VERSION 5.7 ;
  NOWIREEXTENSIONATPIN ON ;
  DIVIDERCHAR "/" ;
  BUSBITCHARS "[]" ;
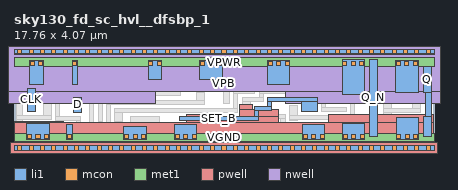
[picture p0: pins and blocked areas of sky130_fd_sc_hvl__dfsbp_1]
MACRO sky130_fd_sc_hvl__dfsbp_1
  CLASS BLOCK ;
  FOREIGN sky130_fd_sc_hvl__dfsbp_1 ;
  ORIGIN 0.000 0.000 ;
  SIZE 17.760 BY 4.070 ;
  PIN CLK
    ANTENNAGATEAREA 0.585000 ;
    PORT
      LAYER li1 ;
        RECT 0.560 1.550 0.890 2.520 ;
    END
  END CLK
  PIN D
    ANTENNAGATEAREA 0.420000 ;
    PORT
      LAYER li1 ;
        RECT 2.525 1.515 2.875 2.145 ;
    END
  END D
  PIN SET_B
    ANTENNAGATEAREA 0.840000 ;
    PORT
      LAYER li1 ;
        RECT 10.715 1.975 12.830 2.145 ;
        RECT 10.715 1.775 10.885 1.975 ;
        RECT 10.160 1.605 10.885 1.775 ;
        RECT 10.160 1.325 10.330 1.605 ;
        RECT 12.150 1.555 12.830 1.975 ;
        RECT 6.985 1.155 10.330 1.325 ;
    END
  END SET_B
  PIN VGND
    USE GROUND ;
    PORT
      LAYER li1 ;
        RECT 0.540 0.365 1.490 1.020 ;
        RECT 2.220 0.365 2.470 0.985 ;
        RECT 4.650 0.365 5.600 0.905 ;
        RECT 6.785 0.365 7.735 0.975 ;
        RECT 12.200 0.365 13.150 0.975 ;
        RECT 13.900 0.365 14.835 1.025 ;
        RECT 16.155 0.365 17.105 1.305 ;
      LAYER mcon ;
        RECT 0.570 0.395 0.740 0.565 ;
        RECT 0.930 0.395 1.100 0.565 ;
        RECT 1.290 0.395 1.460 0.565 ;
        RECT 2.250 0.395 2.420 0.565 ;
        RECT 4.680 0.395 4.850 0.565 ;
        RECT 5.040 0.395 5.210 0.565 ;
        RECT 5.400 0.395 5.570 0.565 ;
        RECT 6.815 0.395 6.985 0.565 ;
        RECT 7.175 0.395 7.345 0.565 ;
        RECT 7.535 0.395 7.705 0.565 ;
        RECT 12.230 0.395 12.400 0.565 ;
        RECT 12.590 0.395 12.760 0.565 ;
        RECT 12.950 0.395 13.120 0.565 ;
        RECT 13.920 0.395 14.090 0.565 ;
        RECT 14.280 0.395 14.450 0.565 ;
        RECT 14.640 0.395 14.810 0.565 ;
        RECT 16.185 0.395 16.355 0.565 ;
        RECT 16.545 0.395 16.715 0.565 ;
        RECT 16.905 0.395 17.075 0.565 ;
      LAYER met1 ;
        RECT 0.000 0.255 17.760 0.625 ;
    END
  END VGND
  PIN VNB
    ANTENNADIFFAREA 3.019200 ;
    PORT
      LAYER pwell ;
        RECT 9.540 1.645 10.090 1.845 ;
        RECT 7.315 1.315 8.605 1.415 ;
        RECT 9.540 1.315 11.200 1.645 ;
        RECT 0.020 1.095 2.090 1.110 ;
        RECT 0.020 1.085 5.690 1.095 ;
        RECT 7.315 1.085 11.200 1.315 ;
        RECT 13.280 1.085 17.740 1.415 ;
        RECT 0.020 0.215 17.740 1.085 ;
        RECT -0.130 -0.215 17.890 0.215 ;
      LAYER li1 ;
        RECT 0.000 -0.085 17.760 0.085 ;
      LAYER mcon ;
        RECT 0.155 -0.085 0.325 0.085 ;
        RECT 0.635 -0.085 0.805 0.085 ;
        RECT 1.115 -0.085 1.285 0.085 ;
        RECT 1.595 -0.085 1.765 0.085 ;
        RECT 2.075 -0.085 2.245 0.085 ;
        RECT 2.555 -0.085 2.725 0.085 ;
        RECT 3.035 -0.085 3.205 0.085 ;
        RECT 3.515 -0.085 3.685 0.085 ;
        RECT 3.995 -0.085 4.165 0.085 ;
        RECT 4.475 -0.085 4.645 0.085 ;
        RECT 4.955 -0.085 5.125 0.085 ;
        RECT 5.435 -0.085 5.605 0.085 ;
        RECT 5.915 -0.085 6.085 0.085 ;
        RECT 6.395 -0.085 6.565 0.085 ;
        RECT 6.875 -0.085 7.045 0.085 ;
        RECT 7.355 -0.085 7.525 0.085 ;
        RECT 7.835 -0.085 8.005 0.085 ;
        RECT 8.315 -0.085 8.485 0.085 ;
        RECT 8.795 -0.085 8.965 0.085 ;
        RECT 9.275 -0.085 9.445 0.085 ;
        RECT 9.755 -0.085 9.925 0.085 ;
        RECT 10.235 -0.085 10.405 0.085 ;
        RECT 10.715 -0.085 10.885 0.085 ;
        RECT 11.195 -0.085 11.365 0.085 ;
        RECT 11.675 -0.085 11.845 0.085 ;
        RECT 12.155 -0.085 12.325 0.085 ;
        RECT 12.635 -0.085 12.805 0.085 ;
        RECT 13.115 -0.085 13.285 0.085 ;
        RECT 13.595 -0.085 13.765 0.085 ;
        RECT 14.075 -0.085 14.245 0.085 ;
        RECT 14.555 -0.085 14.725 0.085 ;
        RECT 15.035 -0.085 15.205 0.085 ;
        RECT 15.515 -0.085 15.685 0.085 ;
        RECT 15.995 -0.085 16.165 0.085 ;
        RECT 16.475 -0.085 16.645 0.085 ;
        RECT 16.955 -0.085 17.125 0.085 ;
        RECT 17.435 -0.085 17.605 0.085 ;
      LAYER met1 ;
        RECT 0.000 -0.115 17.760 0.115 ;
    END
  END VNB
  PIN VPB
    ANTENNADIFFAREA 3.019200 ;
    PORT
      LAYER nwell ;
        RECT -0.330 2.385 18.090 4.485 ;
        RECT -0.330 1.885 5.990 2.385 ;
        RECT 11.500 1.885 18.090 2.385 ;
      LAYER li1 ;
        RECT 0.000 3.985 17.760 4.155 ;
      LAYER mcon ;
        RECT 0.155 3.985 0.325 4.155 ;
        RECT 0.635 3.985 0.805 4.155 ;
        RECT 1.115 3.985 1.285 4.155 ;
        RECT 1.595 3.985 1.765 4.155 ;
        RECT 2.075 3.985 2.245 4.155 ;
        RECT 2.555 3.985 2.725 4.155 ;
        RECT 3.035 3.985 3.205 4.155 ;
        RECT 3.515 3.985 3.685 4.155 ;
        RECT 3.995 3.985 4.165 4.155 ;
        RECT 4.475 3.985 4.645 4.155 ;
        RECT 4.955 3.985 5.125 4.155 ;
        RECT 5.435 3.985 5.605 4.155 ;
        RECT 5.915 3.985 6.085 4.155 ;
        RECT 6.395 3.985 6.565 4.155 ;
        RECT 6.875 3.985 7.045 4.155 ;
        RECT 7.355 3.985 7.525 4.155 ;
        RECT 7.835 3.985 8.005 4.155 ;
        RECT 8.315 3.985 8.485 4.155 ;
        RECT 8.795 3.985 8.965 4.155 ;
        RECT 9.275 3.985 9.445 4.155 ;
        RECT 9.755 3.985 9.925 4.155 ;
        RECT 10.235 3.985 10.405 4.155 ;
        RECT 10.715 3.985 10.885 4.155 ;
        RECT 11.195 3.985 11.365 4.155 ;
        RECT 11.675 3.985 11.845 4.155 ;
        RECT 12.155 3.985 12.325 4.155 ;
        RECT 12.635 3.985 12.805 4.155 ;
        RECT 13.115 3.985 13.285 4.155 ;
        RECT 13.595 3.985 13.765 4.155 ;
        RECT 14.075 3.985 14.245 4.155 ;
        RECT 14.555 3.985 14.725 4.155 ;
        RECT 15.035 3.985 15.205 4.155 ;
        RECT 15.515 3.985 15.685 4.155 ;
        RECT 15.995 3.985 16.165 4.155 ;
        RECT 16.475 3.985 16.645 4.155 ;
        RECT 16.955 3.985 17.125 4.155 ;
        RECT 17.435 3.985 17.605 4.155 ;
      LAYER met1 ;
        RECT 0.000 3.955 17.760 4.185 ;
    END
  END VPB
  PIN VPWR
    USE POWER ;
    PORT
      LAYER li1 ;
        RECT 0.650 2.700 1.240 3.705 ;
        RECT 2.470 2.675 2.675 3.705 ;
        RECT 5.680 2.905 6.245 3.705 ;
        RECT 7.855 2.895 8.805 3.705 ;
        RECT 10.715 2.675 11.665 3.705 ;
        RECT 13.870 2.255 14.820 3.755 ;
        RECT 16.135 2.355 17.085 3.705 ;
      LAYER mcon ;
        RECT 0.680 3.505 0.850 3.675 ;
        RECT 1.040 3.505 1.210 3.675 ;
        RECT 2.490 3.505 2.660 3.675 ;
        RECT 5.695 3.505 5.865 3.675 ;
        RECT 6.055 3.505 6.225 3.675 ;
        RECT 7.885 3.505 8.055 3.675 ;
        RECT 8.245 3.505 8.415 3.675 ;
        RECT 8.605 3.505 8.775 3.675 ;
        RECT 10.745 3.505 10.915 3.675 ;
        RECT 11.105 3.505 11.275 3.675 ;
        RECT 11.465 3.505 11.635 3.675 ;
        RECT 13.900 3.505 14.070 3.675 ;
        RECT 14.260 3.505 14.430 3.675 ;
        RECT 14.620 3.505 14.790 3.675 ;
        RECT 16.165 3.505 16.335 3.675 ;
        RECT 16.525 3.505 16.695 3.675 ;
        RECT 16.885 3.505 17.055 3.675 ;
      LAYER met1 ;
        RECT 0.000 3.445 17.760 3.815 ;
    END
  END VPWR
  PIN Q
    ANTENNADIFFAREA 0.498750 ;
    PORT
      LAYER li1 ;
        RECT 17.300 2.355 17.635 3.435 ;
        RECT 17.405 1.325 17.635 2.355 ;
        RECT 17.300 0.495 17.635 1.325 ;
    END
  END Q
  PIN Q_N
    ANTENNADIFFAREA 0.641250 ;
    PORT
      LAYER li1 ;
        RECT 15.015 0.495 15.375 3.755 ;
    END
  END Q_N
  OBS
      LAYER li1 ;
        RECT 1.420 3.630 2.290 3.800 ;
        RECT 0.110 1.370 0.380 3.450 ;
        RECT 1.420 1.870 1.590 3.630 ;
        RECT 1.260 1.370 1.590 1.870 ;
        RECT 0.110 1.200 1.590 1.370 ;
        RECT 1.770 1.335 1.940 3.450 ;
        RECT 2.120 2.495 2.290 3.630 ;
        RECT 9.345 3.585 10.535 3.755 ;
        RECT 2.855 3.355 5.500 3.525 ;
        RECT 2.855 2.495 3.025 3.355 ;
        RECT 2.120 2.325 3.025 2.495 ;
        RECT 3.205 2.675 3.545 3.175 ;
        RECT 0.110 0.540 0.360 1.200 ;
        RECT 1.770 1.165 2.820 1.335 ;
        RECT 1.770 1.000 2.000 1.165 ;
        RECT 1.670 0.540 2.000 1.000 ;
        RECT 2.650 0.435 2.820 1.165 ;
        RECT 3.205 1.005 3.375 2.675 ;
        RECT 3.725 2.395 3.895 3.355 ;
        RECT 4.075 3.005 5.150 3.175 ;
        RECT 4.075 2.675 4.405 3.005 ;
        RECT 4.585 2.395 4.800 2.555 ;
        RECT 3.555 2.225 4.800 2.395 ;
        RECT 3.555 1.105 3.725 2.225 ;
        RECT 4.980 2.025 5.150 3.005 ;
        RECT 5.330 2.725 5.500 3.355 ;
        RECT 6.425 3.355 7.675 3.525 ;
        RECT 6.425 2.725 6.595 3.355 ;
        RECT 5.330 2.555 6.595 2.725 ;
        RECT 6.775 2.375 7.025 3.175 ;
        RECT 7.505 2.715 7.675 3.355 ;
        RECT 7.505 2.545 9.120 2.715 ;
        RECT 9.345 2.675 9.675 3.585 ;
        RECT 5.330 2.205 7.025 2.375 ;
        RECT 7.730 2.025 8.060 2.365 ;
        RECT 3.905 1.855 8.060 2.025 ;
        RECT 8.870 1.885 9.120 2.545 ;
        RECT 9.855 2.475 10.185 2.555 ;
        RECT 9.300 2.305 10.185 2.475 ;
        RECT 10.365 2.495 10.535 3.585 ;
        RECT 12.035 2.495 13.180 3.175 ;
        RECT 10.365 2.325 13.180 2.495 ;
        RECT 3.000 0.615 3.375 1.005 ;
        RECT 3.905 0.925 4.075 1.855 ;
        RECT 9.300 1.675 9.470 2.305 ;
        RECT 10.365 2.125 10.535 2.325 ;
        RECT 4.255 1.505 9.470 1.675 ;
        RECT 9.650 1.955 10.535 2.125 ;
        RECT 9.650 1.505 9.980 1.955 ;
        RECT 4.255 1.105 4.585 1.505 ;
        RECT 3.780 0.615 4.110 0.925 ;
        RECT 4.290 0.435 4.460 1.105 ;
        RECT 4.945 1.085 6.150 1.325 ;
        RECT 5.820 0.515 6.150 1.085 ;
        RECT 10.510 1.255 11.460 1.425 ;
        RECT 10.510 0.975 10.680 1.255 ;
        RECT 8.185 0.545 8.515 0.975 ;
        RECT 8.755 0.725 10.680 0.975 ;
        RECT 10.860 0.545 11.110 1.075 ;
        RECT 2.650 0.265 4.460 0.435 ;
        RECT 8.185 0.375 11.110 0.545 ;
        RECT 11.290 0.975 11.460 1.255 ;
        RECT 11.640 1.375 11.970 1.795 ;
        RECT 13.010 1.725 13.180 2.325 ;
        RECT 13.360 2.075 13.690 2.675 ;
        RECT 13.360 1.905 14.395 2.075 ;
        RECT 13.010 1.555 14.045 1.725 ;
        RECT 14.225 1.375 14.395 1.905 ;
        RECT 11.640 1.205 14.395 1.375 ;
        RECT 15.625 1.675 15.955 3.185 ;
        RECT 16.845 1.675 17.175 2.175 ;
        RECT 15.625 1.505 17.175 1.675 ;
        RECT 11.640 1.155 11.970 1.205 ;
        RECT 11.290 0.515 11.660 0.975 ;
        RECT 13.390 0.825 13.720 1.205 ;
        RECT 15.625 0.825 15.975 1.505 ;
  END
END sky130_fd_sc_hvl__dfsbp_1
END LIBRARY

